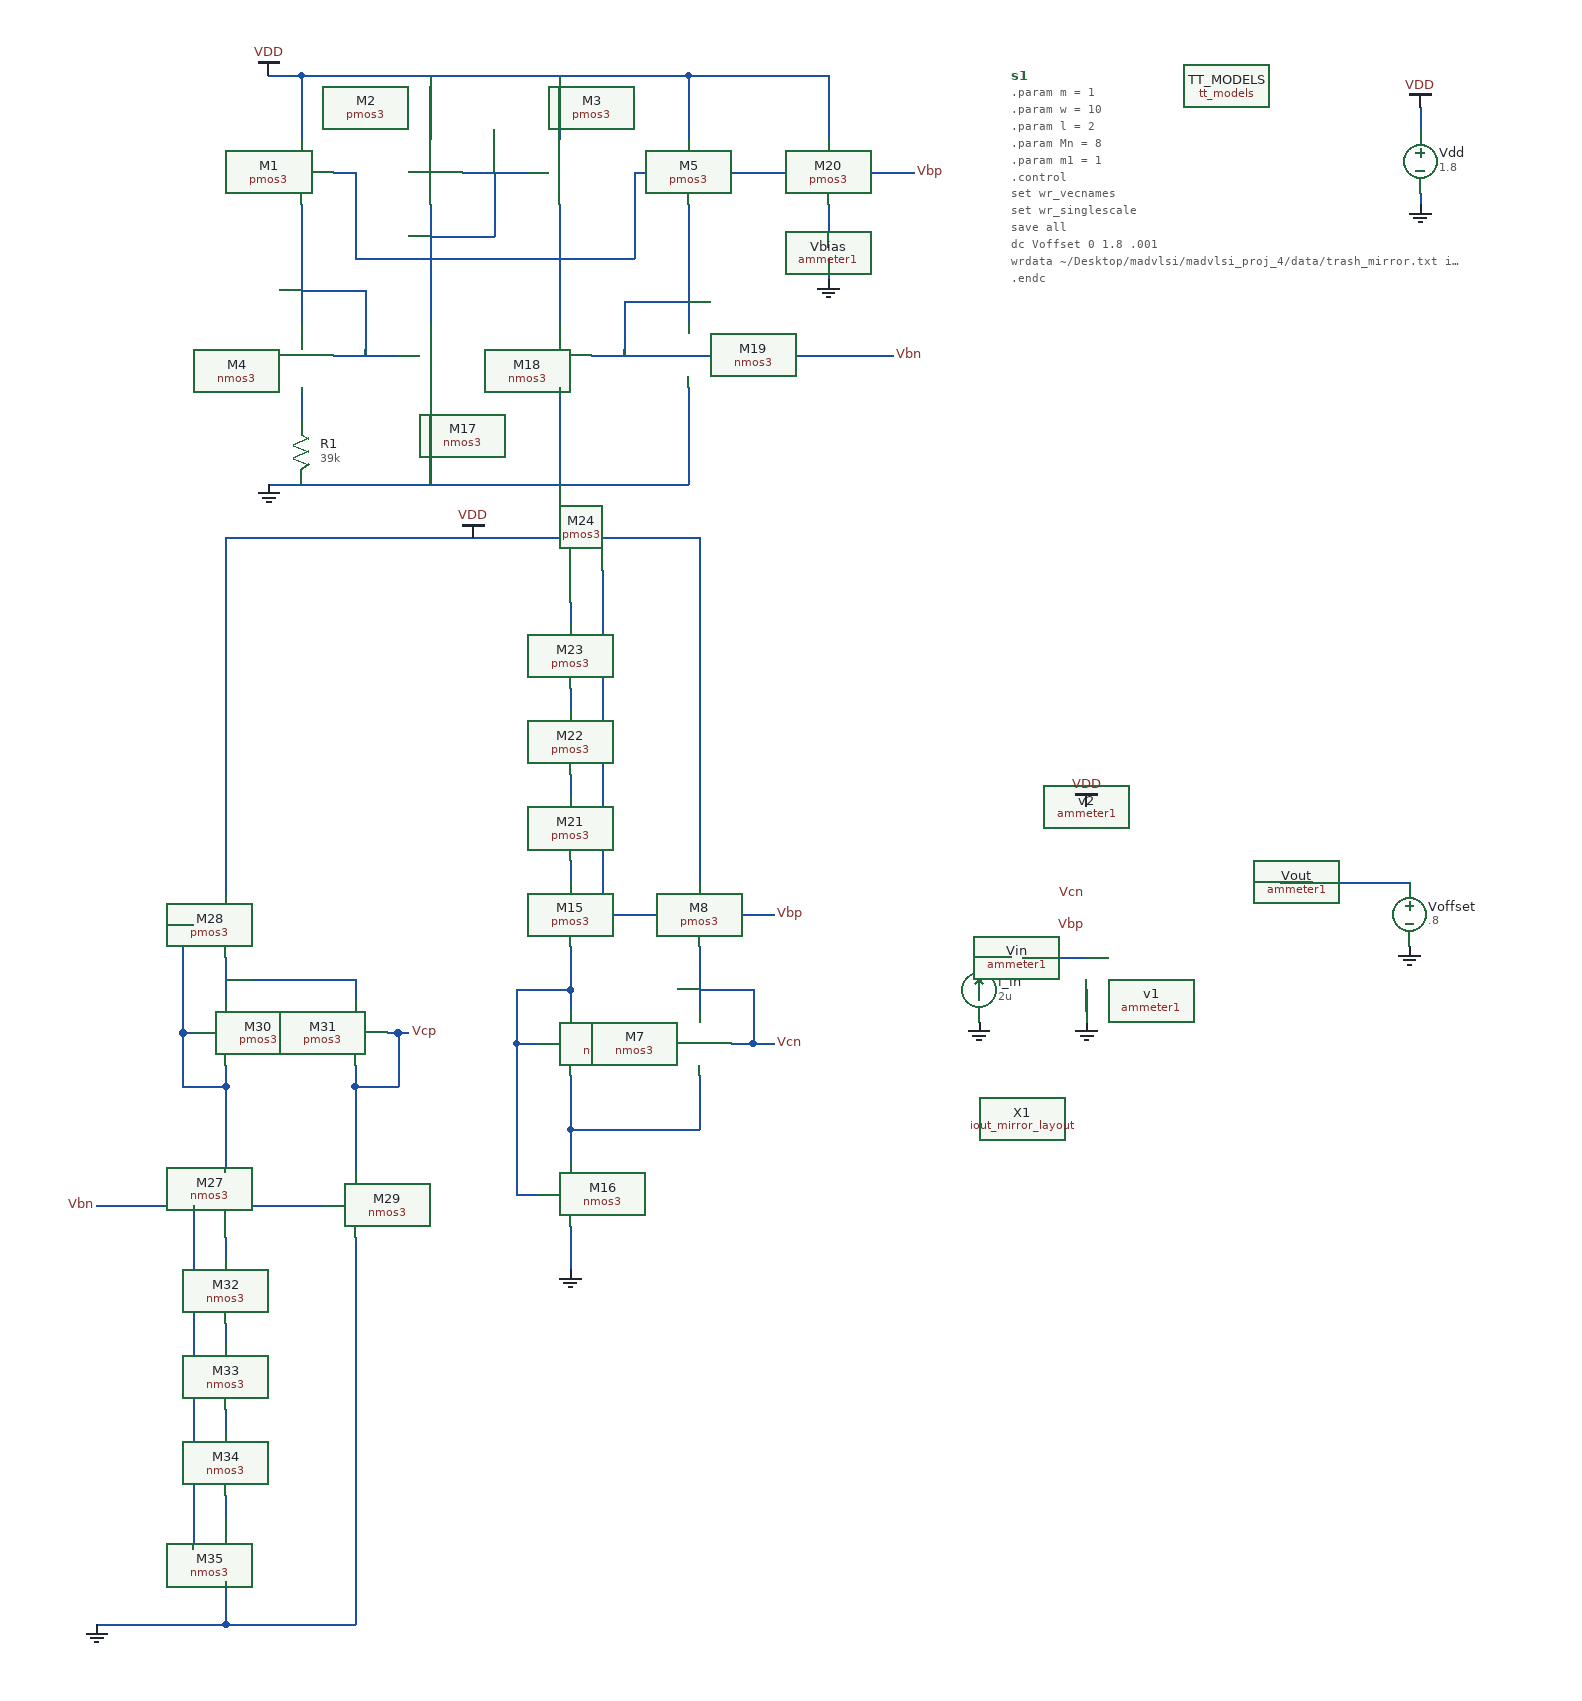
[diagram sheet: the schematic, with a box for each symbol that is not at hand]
v {xschem version=2.9.9 file_version=1.2 }
G {}
K {}
V {}
S {}
E {}
N 900 -880 900 -870 { lab=GND}
N 900 -960 900 -940 { lab=VDD}
N 60 -90 80 -90 { lab=#net1}
N 60 -90 60 50 { lab=#net1}
N 60 50 80 50 { lab=#net1}
N 60 -140 60 -90 { lab=#net1}
N 60 -140 110 -140 { lab=#net1}
N 110 -140 110 -120 { lab=#net1}
N 110 -180 110 -140 { lab=#net1}
N 230 -180 230 -120 { lab=Vcn}
N 230 -140 280 -140 { lab=Vcn}
N 280 -140 280 -90 { lab=Vcn}
N 260 -90 280 -90 { lab=Vcn}
N 230 -60 230 -10 { lab=#net2}
N 110 -10 230 -10 { lab=#net2}
N 110 -10 110 20 { lab=#net2}
N 110 -60 110 -10 { lab=#net2}
N 110 80 110 120 { lab=GND}
N 280 -90 300 -90 { lab=Vcn}
N 140 -530 140 -210 { lab=Vbp}
N 110 -260 110 -240 { lab=#net3}
N 110 -340 110 -320 { lab=#net4}
N 110 -420 110 -400 { lab=#net5}
N 110 -500 110 -480 { lab=#net6}
N 230 -560 230 -240 { lab=VDD}
N 140 -210 300 -210 { lab=Vbp}
N 20 -560 230 -560 { lab=VDD}
N -20 -700 -20 -670 { lab=GND}
N 100 -700 100 -670 { lab=GND}
N 220 -700 220 -670 { lab=GND}
N -140 -700 -140 -670 { lab=#net7}
N -140 -870 -140 -760 { lab=#net8}
N -20 -870 -20 -760 { lab=#net9}
N 100 -870 100 -760 { lab=Vbp}
N -110 -730 -50 -730 { lab=#net8}
N 130 -730 190 -730 { lab=Vbn}
N -140 -790 -80 -790 { lab=#net8}
N -80 -790 -80 -730 { lab=#net8}
N 10 -900 70 -900 { lab=#net9}
N 40 -900 40 -840 { lab=#net9}
N -20 -840 40 -840 { lab=#net9}
N -110 -900 -90 -900 { lab=Vbp}
N -90 -900 -90 -820 { lab=Vbp}
N -90 -820 100 -820 { lab=Vbp}
N 100 -820 170 -820 { lab=Vbp}
N 170 -900 170 -820 { lab=Vbp}
N 170 -900 190 -900 { lab=Vbp}
N 160 -780 160 -730 { lab=Vbn}
N 160 -780 220 -780 { lab=Vbn}
N -20 -990 -20 -930 { lab=VDD}
N 100 -990 100 -930 { lab=VDD}
N 220 -990 220 -930 { lab=VDD}
N 220 -670 220 -610 { lab=GND}
N 100 -670 100 -610 { lab=GND}
N -20 -670 -20 -610 { lab=GND}
N 220 -830 220 -760 { lab=Vbn}
N 220 -870 220 -840 { lab=Vbn}
N -140 -610 220 -610 { lab=GND}
N -140 -990 220 -990 { lab=VDD}
N -140 -990 -140 -930 { lab=VDD}
N -170 -990 -140 -990 { lab=VDD}
N -170 -610 -140 -610 { lab=GND}
N 220 -840 220 -830 { lab=Vbn}
N 190 -900 320 -900 { lab=Vbp}
N 320 -900 430 -900 { lab=Vbp}
N 350 -870 350 -830 { lab=#net10}
N 350 -990 350 -930 { lab=VDD}
N 220 -990 350 -990 { lab=VDD}
N 350 -820 350 -800 { lab=GND}
N -210 -170 -210 -130 { lab=#net11}
N -90 -150 -90 -130 { lab=#net11}
N -210 -150 -90 -150 { lab=#net11}
N -250 -50 -210 -50 { lab=#net12}
N -250 -100 -250 -50 { lab=#net12}
N -250 -100 -240 -100 { lab=#net12}
N -250 -200 -250 -100 { lab=#net12}
N -250 -200 -240 -200 { lab=#net12}
N -210 -70 -210 -50 { lab=#net12}
N -60 -100 -50 -100 { lab=Vcp}
N -50 -100 -50 -50 { lab=Vcp}
N -90 -50 -50 -50 { lab=Vcp}
N -90 -70 -90 -50 { lab=Vcp}
N -90 -50 -90 30 { lab=Vcp}
N -210 -50 -210 30 { lab=#net12}
N -210 -280 -210 -230 { lab=VDD}
N -330 450 -320 450 { lab=GND}
N -50 -100 -40 -100 { lab=Vcp}
N -210 90 -210 110 { lab=#net13}
N -210 170 -210 190 { lab=#net14}
N -210 250 -210 270 { lab=#net15}
N -210 330 -210 350 { lab=#net16}
N -240 60 -240 380 { lab=Vbn}
N -320 450 -210 450 { lab=GND}
N -210 450 -90 450 { lab=GND}
N -210 -550 -210 -280 { lab=VDD}
N -330 60 -120 60 { lab=Vbn}
N -90 410 -90 450 { lab=GND}
N -210 410 -210 450 { lab=GND}
N -90 90 -90 410 { lab=GND}
N -210 -560 20 -560 { lab=VDD}
N -210 -560 -210 -550 { lab=VDD}
N 190 -730 410 -730 { lab=Vbn}
N 490 -170 520 -170 { lab=#net17}
N 810 -240 890 -240 { lab=#net19}
N 530 -170 590 -170 { lab=#net20}
N 590 -140 590 -120 { lab=#net21}
N 770 -240 800 -240 { lab=#net22}
C {devices/code_shown.sym} 520 -990 0 0 {name=s1 only_toplevel=false value="

.param m = 1
.param w = 10
.param l = 2
.param Mn = 8
.param m1 = 1

.control
set wr_vecnames
set wr_singlescale
save all
dc Voffset 0 1.8 .001
wrdata ~/Desktop/madvlsi/madvlsi_proj_4/data/trash_mirror.txt i(Vin) i(Vout) i(Vbias) i(v1) i(v2) v(Vbp) v(Vcn)
.endc
"}
C {madvlsi/tt_models.sym} 720 -980 0 0 {
name=TT_MODELS
only_toplevel=false
value=".option wnflag=1
.param MC_SWITCH=0.0
.lib ~/skywater/skywater-pdk/libraries/sky130_fd_pr_ngspice/latest/models/sky130.lib.spice tt"
}
C {madvlsi/vsource.sym} 900 -910 0 0 {name=Vdd
value=1.8}
C {madvlsi/gnd.sym} 900 -870 0 0 {name=l19 lab=GND}
C {madvlsi/vdd.sym} 900 -960 0 0 {name=l20 lab=VDD}
C {madvlsi/nmos3.sym} 110 -90 0 0 {name=M6
L=l
W=w
body=GND
nf=1
mult=m*4
ad="'int((nf+1)/2) * W/nf * 0.29'" 
pd="'2*int((nf+1)/2) * (W/nf + 0.29)'"
as="'int((nf+2)/2) * W/nf * 0.29'" 
ps="'2*int((nf+2)/2) * (W/nf + 0.29)'"
nrd="'0.29 / W'" nrs="'0.29 / W'"
sa=0 sb=0 sd=0
model=nfet_01v8
spiceprefix=X
}
C {madvlsi/nmos3.sym} 230 -90 2 0 {name=M7
L=l
W=w
body=GND
nf=1
mult=m
ad="'int((nf+1)/2) * W/nf * 0.29'" 
pd="'2*int((nf+1)/2) * (W/nf + 0.29)'"
as="'int((nf+2)/2) * W/nf * 0.29'" 
ps="'2*int((nf+2)/2) * (W/nf + 0.29)'"
nrd="'0.29 / W'" nrs="'0.29 / W'"
sa=0 sb=0 sd=0
model=nfet_01v8
spiceprefix=X
}
C {madvlsi/pmos3.sym} 230 -210 0 0 {name=M8
L=l
W=w
body=VDD
nf=1
mult=m
ad="'int((nf+1)/2) * W/nf * 0.29'" 
pd="'2*int((nf+1)/2) * (W/nf + 0.29)'"
as="'int((nf+2)/2) * W/nf * 0.29'" 
ps="'2*int((nf+2)/2) * (W/nf + 0.29)'"
nrd="'0.29 / W'" nrs="'0.29 / W'"
sa=0 sb=0 sd=0
model=pfet_01v8
spiceprefix=X
}
C {madvlsi/pmos3.sym} 110 -210 2 0 {name=M15
L=l
W=w
body=VDD
nf=1
mult=m
ad="'int((nf+1)/2) * W/nf * 0.29'" 
pd="'2*int((nf+1)/2) * (W/nf + 0.29)'"
as="'int((nf+2)/2) * W/nf * 0.29'" 
ps="'2*int((nf+2)/2) * (W/nf + 0.29)'"
nrd="'0.29 / W'" nrs="'0.29 / W'"
sa=0 sb=0 sd=0
model=pfet_01v8
spiceprefix=X
}
C {madvlsi/nmos3.sym} 110 50 0 0 {name=M16
L=l
W=w
body=GND
nf=1
mult=m
ad="'int((nf+1)/2) * W/nf * 0.29'" 
pd="'2*int((nf+1)/2) * (W/nf + 0.29)'"
as="'int((nf+2)/2) * W/nf * 0.29'" 
ps="'2*int((nf+2)/2) * (W/nf + 0.29)'"
nrd="'0.29 / W'" nrs="'0.29 / W'"
sa=0 sb=0 sd=0
model=nfet_01v8
spiceprefix=X
}
C {madvlsi/pmos3.sym} 110 -290 2 0 {name=M21
L=l
W=w
body=VDD
nf=1
mult=m
ad="'int((nf+1)/2) * W/nf * 0.29'" 
pd="'2*int((nf+1)/2) * (W/nf + 0.29)'"
as="'int((nf+2)/2) * W/nf * 0.29'" 
ps="'2*int((nf+2)/2) * (W/nf + 0.29)'"
nrd="'0.29 / W'" nrs="'0.29 / W'"
sa=0 sb=0 sd=0
model=pfet_01v8
spiceprefix=X
}
C {madvlsi/pmos3.sym} 110 -370 2 0 {name=M22
L=l
W=w
body=VDD
nf=1
mult=m
ad="'int((nf+1)/2) * W/nf * 0.29'" 
pd="'2*int((nf+1)/2) * (W/nf + 0.29)'"
as="'int((nf+2)/2) * W/nf * 0.29'" 
ps="'2*int((nf+2)/2) * (W/nf + 0.29)'"
nrd="'0.29 / W'" nrs="'0.29 / W'"
sa=0 sb=0 sd=0
model=pfet_01v8
spiceprefix=X
}
C {madvlsi/pmos3.sym} 110 -450 2 0 {name=M23
L=l
W=w
body=VDD
nf=1
mult=m
ad="'int((nf+1)/2) * W/nf * 0.29'" 
pd="'2*int((nf+1)/2) * (W/nf + 0.29)'"
as="'int((nf+2)/2) * W/nf * 0.29'" 
ps="'2*int((nf+2)/2) * (W/nf + 0.29)'"
nrd="'0.29 / W'" nrs="'0.29 / W'"
sa=0 sb=0 sd=0
model=pfet_01v8
spiceprefix=X
}
C {madvlsi/pmos3.sym} 110 -530 2 0 {name=M24
L=l
W=w
body=VDD
nf=1
mult=m
ad="'int((nf+1)/2) * W/nf * 0.29'" 
pd="'2*int((nf+1)/2) * (W/nf + 0.29)'"
as="'int((nf+2)/2) * W/nf * 0.29'" 
ps="'2*int((nf+2)/2) * (W/nf + 0.29)'"
nrd="'0.29 / W'" nrs="'0.29 / W'"
sa=0 sb=0 sd=0
model=pfet_01v8
spiceprefix=X
}
C {devices/lab_pin.sym} 300 -210 2 0 {name=l1 sig_type=std_logic lab=Vbp}
C {madvlsi/gnd.sym} 110 120 0 0 {name=l2 lab=GND}
C {madvlsi/vdd.sym} 20 -560 0 0 {name=l5 lab=VDD}
C {devices/lab_pin.sym} 300 -90 2 0 {name=l6 sig_type=std_logic lab=Vcn}
C {madvlsi/pmos3.sym} -140 -900 2 0 {name=M1
L=l
W=w
body=VDD
nf=1
mult=1
ad="'int((nf+1)/2) * W/nf * 0.29'" 
pd="'2*int((nf+1)/2) * (W/nf + 0.29)'"
as="'int((nf+2)/2) * W/nf * 0.29'" 
ps="'2*int((nf+2)/2) * (W/nf + 0.29)'"
nrd="'0.29 / W'" nrs="'0.29 / W'"
sa=0 sb=0 sd=0
model=pfet_01v8
spiceprefix=X
}
C {madvlsi/pmos3.sym} -20 -900 2 0 {name=M2
L=l
W=w
body=VDD
nf=1
mult=1
ad="'int((nf+1)/2) * W/nf * 0.29'" 
pd="'2*int((nf+1)/2) * (W/nf + 0.29)'"
as="'int((nf+2)/2) * W/nf * 0.29'" 
ps="'2*int((nf+2)/2) * (W/nf + 0.29)'"
nrd="'0.29 / W'" nrs="'0.29 / W'"
sa=0 sb=0 sd=0
model=pfet_01v8
spiceprefix=X
}
C {madvlsi/pmos3.sym} 100 -900 0 0 {name=M3
L=l
W=w
body=VDD
nf=1
mult=1
ad="'int((nf+1)/2) * W/nf * 0.29'" 
pd="'2*int((nf+1)/2) * (W/nf + 0.29)'"
as="'int((nf+2)/2) * W/nf * 0.29'" 
ps="'2*int((nf+2)/2) * (W/nf + 0.29)'"
nrd="'0.29 / W'" nrs="'0.29 / W'"
sa=0 sb=0 sd=0
model=pfet_01v8
spiceprefix=X
}
C {madvlsi/pmos3.sym} 220 -900 0 0 {name=M5
L=l
W=w
body=VDD
nf=1
mult=1
ad="'int((nf+1)/2) * W/nf * 0.29'" 
pd="'2*int((nf+1)/2) * (W/nf + 0.29)'"
as="'int((nf+2)/2) * W/nf * 0.29'" 
ps="'2*int((nf+2)/2) * (W/nf + 0.29)'"
nrd="'0.29 / W'" nrs="'0.29 / W'"
sa=0 sb=0 sd=0
model=pfet_01v8
spiceprefix=X
}
C {madvlsi/nmos3.sym} -140 -730 2 0 {name=M4
L=l
W=w
body=GND
nf=1
mult=Mn
ad="'int((nf+1)/2) * W/nf * 0.29'" 
pd="'2*int((nf+1)/2) * (W/nf + 0.29)'"
as="'int((nf+2)/2) * W/nf * 0.29'" 
ps="'2*int((nf+2)/2) * (W/nf + 0.29)'"
nrd="'0.29 / W'" nrs="'0.29 / W'"
sa=0 sb=0 sd=0
model=nfet_01v8
spiceprefix=X
}
C {madvlsi/nmos3.sym} -20 -730 0 0 {name=M17
L=l
W=w
body=GND
nf=1
mult=1
ad="'int((nf+1)/2) * W/nf * 0.29'" 
pd="'2*int((nf+1)/2) * (W/nf + 0.29)'"
as="'int((nf+2)/2) * W/nf * 0.29'" 
ps="'2*int((nf+2)/2) * (W/nf + 0.29)'"
nrd="'0.29 / W'" nrs="'0.29 / W'"
sa=0 sb=0 sd=0
model=nfet_01v8
spiceprefix=X
}
C {madvlsi/nmos3.sym} 100 -730 2 0 {name=M18
L=l
W=w
body=GND
nf=1
mult=1
ad="'int((nf+1)/2) * W/nf * 0.29'" 
pd="'2*int((nf+1)/2) * (W/nf + 0.29)'"
as="'int((nf+2)/2) * W/nf * 0.29'" 
ps="'2*int((nf+2)/2) * (W/nf + 0.29)'"
nrd="'0.29 / W'" nrs="'0.29 / W'"
sa=0 sb=0 sd=0
model=nfet_01v8
spiceprefix=X
}
C {madvlsi/nmos3.sym} 220 -730 0 0 {name=M19
L=l
W=w
body=GND
nf=1
mult=1
ad="'int((nf+1)/2) * W/nf * 0.29'" 
pd="'2*int((nf+1)/2) * (W/nf + 0.29)'"
as="'int((nf+2)/2) * W/nf * 0.29'" 
ps="'2*int((nf+2)/2) * (W/nf + 0.29)'"
nrd="'0.29 / W'" nrs="'0.29 / W'"
sa=0 sb=0 sd=0
model=nfet_01v8
spiceprefix=X
}
C {madvlsi/resistor.sym} -140 -640 0 0 {name=R1
value=39k
m=1}
C {madvlsi/pmos3.sym} 350 -900 0 0 {name=M20
L=l
W=w
body=VDD
nf=1
mult=m1
ad="'int((nf+1)/2) * W/nf * 0.29'" 
pd="'2*int((nf+1)/2) * (W/nf + 0.29)'"
as="'int((nf+2)/2) * W/nf * 0.29'" 
ps="'2*int((nf+2)/2) * (W/nf + 0.29)'"
nrd="'0.29 / W'" nrs="'0.29 / W'"
sa=0 sb=0 sd=0
model=pfet_01v8
spiceprefix=X
}
C {madvlsi/gnd.sym} 350 -800 0 0 {name=l9 lab=GND}
C {madvlsi/ammeter1.sym} 350 -830 0 0 {name=Vbias}
C {devices/lab_pin.sym} 430 -900 2 0 {name=l10 sig_type=std_logic lab=Vbp}
C {madvlsi/vdd.sym} -170 -990 0 0 {name=l4 lab=VDD}
C {madvlsi/gnd.sym} -170 -610 0 0 {name=l7 lab=GND}
C {madvlsi/nmos3.sym} -210 60 0 0 {name=M27
L=l
W=w
body=GND
nf=1
mult=m
ad="'int((nf+1)/2) * W/nf * 0.29'" 
pd="'2*int((nf+1)/2) * (W/nf + 0.29)'"
as="'int((nf+2)/2) * W/nf * 0.29'" 
ps="'2*int((nf+2)/2) * (W/nf + 0.29)'"
nrd="'0.29 / W'" nrs="'0.29 / W'"
sa=0 sb=0 sd=0
model=nfet_01v8
spiceprefix=X
}
C {madvlsi/pmos3.sym} -210 -200 0 0 {name=M28
L=l
W=w
body=VDD
nf=1
mult=m
ad="'int((nf+1)/2) * W/nf * 0.29'" 
pd="'2*int((nf+1)/2) * (W/nf + 0.29)'"
as="'int((nf+2)/2) * W/nf * 0.29'" 
ps="'2*int((nf+2)/2) * (W/nf + 0.29)'"
nrd="'0.29 / W'" nrs="'0.29 / W'"
sa=0 sb=0 sd=0
model=pfet_01v8
spiceprefix=X
}
C {madvlsi/nmos3.sym} -90 60 0 0 {name=M29
L=l
W=w
body=GND
nf=1
mult=m
ad="'int((nf+1)/2) * W/nf * 0.29'" 
pd="'2*int((nf+1)/2) * (W/nf + 0.29)'"
as="'int((nf+2)/2) * W/nf * 0.29'" 
ps="'2*int((nf+2)/2) * (W/nf + 0.29)'"
nrd="'0.29 / W'" nrs="'0.29 / W'"
sa=0 sb=0 sd=0
model=nfet_01v8
spiceprefix=X
}
C {madvlsi/pmos3.sym} -210 -100 0 0 {name=M30
L=l
W=w
body=VDD
nf=1
mult=m*4
ad="'int((nf+1)/2) * W/nf * 0.29'" 
pd="'2*int((nf+1)/2) * (W/nf + 0.29)'"
as="'int((nf+2)/2) * W/nf * 0.29'" 
ps="'2*int((nf+2)/2) * (W/nf + 0.29)'"
nrd="'0.29 / W'" nrs="'0.29 / W'"
sa=0 sb=0 sd=0
model=pfet_01v8
spiceprefix=X
}
C {madvlsi/pmos3.sym} -90 -100 2 0 {name=M31
L=l
W=w
body=VDD
nf=1
mult=m
ad="'int((nf+1)/2) * W/nf * 0.29'" 
pd="'2*int((nf+1)/2) * (W/nf + 0.29)'"
as="'int((nf+2)/2) * W/nf * 0.29'" 
ps="'2*int((nf+2)/2) * (W/nf + 0.29)'"
nrd="'0.29 / W'" nrs="'0.29 / W'"
sa=0 sb=0 sd=0
model=pfet_01v8
spiceprefix=X
}
C {madvlsi/nmos3.sym} -210 140 0 0 {name=M32
L=l
W=w
body=GND
nf=1
mult=m
ad="'int((nf+1)/2) * W/nf * 0.29'" 
pd="'2*int((nf+1)/2) * (W/nf + 0.29)'"
as="'int((nf+2)/2) * W/nf * 0.29'" 
ps="'2*int((nf+2)/2) * (W/nf + 0.29)'"
nrd="'0.29 / W'" nrs="'0.29 / W'"
sa=0 sb=0 sd=0
model=nfet_01v8
spiceprefix=X
}
C {madvlsi/nmos3.sym} -210 220 0 0 {name=M33
L=l
W=w
body=GND
nf=1
mult=m
ad="'int((nf+1)/2) * W/nf * 0.29'" 
pd="'2*int((nf+1)/2) * (W/nf + 0.29)'"
as="'int((nf+2)/2) * W/nf * 0.29'" 
ps="'2*int((nf+2)/2) * (W/nf + 0.29)'"
nrd="'0.29 / W'" nrs="'0.29 / W'"
sa=0 sb=0 sd=0
model=nfet_01v8
spiceprefix=X
}
C {madvlsi/nmos3.sym} -210 300 0 0 {name=M34
L=l
W=w
body=GND
nf=1
mult=m
ad="'int((nf+1)/2) * W/nf * 0.29'" 
pd="'2*int((nf+1)/2) * (W/nf + 0.29)'"
as="'int((nf+2)/2) * W/nf * 0.29'" 
ps="'2*int((nf+2)/2) * (W/nf + 0.29)'"
nrd="'0.29 / W'" nrs="'0.29 / W'"
sa=0 sb=0 sd=0
model=nfet_01v8
spiceprefix=X
}
C {madvlsi/nmos3.sym} -210 380 0 0 {name=M35
L=l
W=w
body=GND
nf=1
mult=m
ad="'int((nf+1)/2) * W/nf * 0.29'" 
pd="'2*int((nf+1)/2) * (W/nf + 0.29)'"
as="'int((nf+2)/2) * W/nf * 0.29'" 
ps="'2*int((nf+2)/2) * (W/nf + 0.29)'"
nrd="'0.29 / W'" nrs="'0.29 / W'"
sa=0 sb=0 sd=0
model=nfet_01v8
spiceprefix=X
}
C {devices/lab_pin.sym} -40 -100 2 0 {name=l12 sig_type=std_logic lab=Vcp}
C {madvlsi/gnd.sym} -330 450 0 0 {name=l14 lab=GND}
C {devices/lab_pin.sym} -330 60 0 0 {name=l15 sig_type=std_logic lab=Vbn}
C {devices/lab_pin.sym} 410 -730 2 0 {name=l16 sig_type=std_logic lab=Vbn}
C {devices/lab_pin.sym} 590 -230 0 0 {name=l17 sig_type=std_logic lab=Vcn}
C {madvlsi/gnd.sym} 590 -110 0 0 {name=l21 lab=GND}
C {madvlsi/isource.sym} 490 -140 2 0 {name=i_in
value=2u}
C {madvlsi/gnd.sym} 490 -110 0 0 {name=l24 lab=GND}
C {madvlsi/ammeter1.sym} 810 -240 1 0 {name=Vout}
C {madvlsi/ammeter1.sym} 520 -170 3 0 {name=Vin}
C {madvlsi/ammeter1.sym} 590 -310 0 0 {name=v2}
C {madvlsi/ammeter1.sym} 590 -120 0 0 {name=v1}
C {madvlsi/gnd.sym} 890 -180 0 0 {name=l3 lab=GND}
C {madvlsi/vsource.sym} 890 -210 0 0 {name=Voffset
value=.8}
C {/home/madvlsi/Desktop/madvlsi/madvlsi_proj_4/schematic/iout_mirror_layout.sym} 530 -20 0 0 {name=X1}
C {madvlsi/vdd.sym} 590 -310 0 0 {name=l8 lab=VDD}
C {devices/lab_pin.sym} 590 -200 0 0 {name=l11 sig_type=std_logic lab=Vbp}
